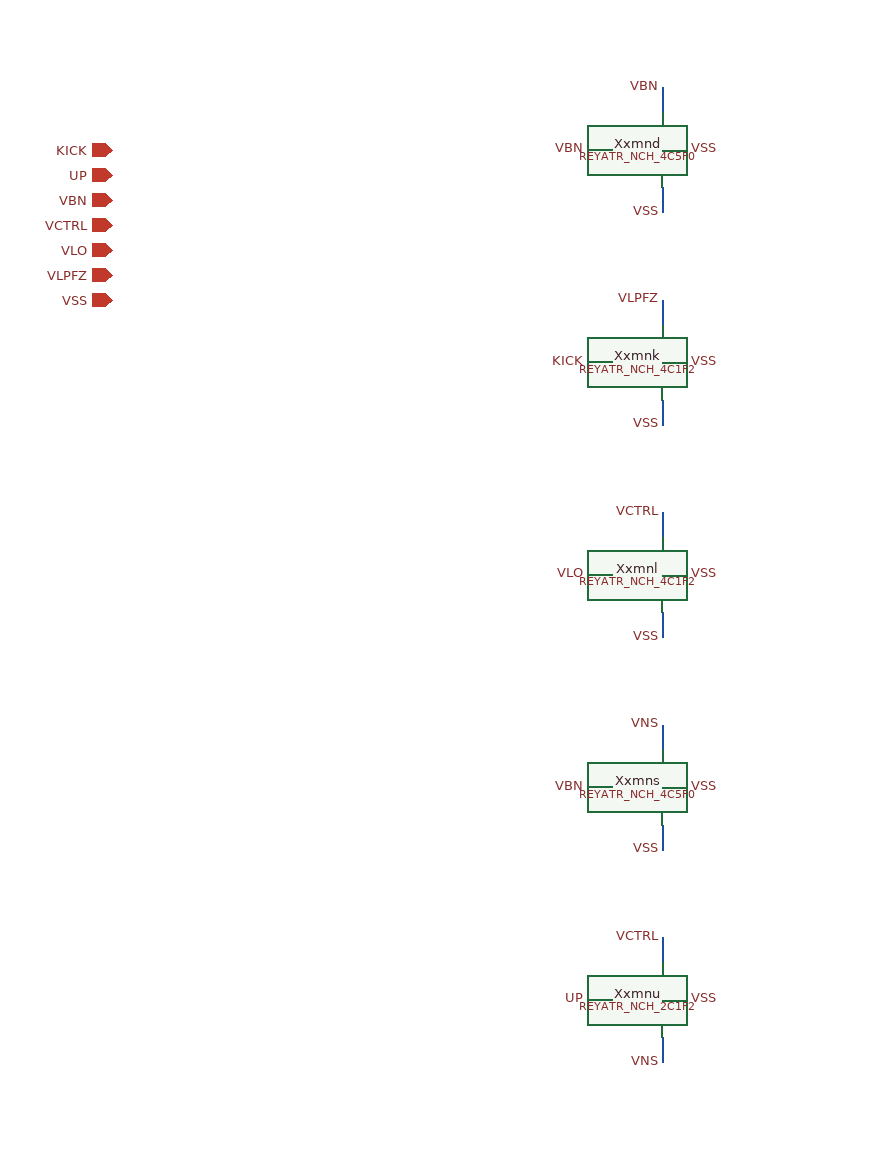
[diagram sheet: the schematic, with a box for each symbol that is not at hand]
v {xschem version=3.0.0 file_version=1.2 }
G {}
K {}
V {}
S {}
E {}
C {devices/iopin.sym} 0 0 0 0 {name=p0 lab=KICK}
C {devices/iopin.sym} 0 20 0 0 {name=p1 lab=UP}
C {devices/iopin.sym} 0 40 0 0 {name=p2 lab=VBN}
C {devices/iopin.sym} 0 60 0 0 {name=p3 lab=VCTRL}
C {devices/iopin.sym} 0 80 0 0 {name=p4 lab=VLO}
C {devices/iopin.sym} 0 100 0 0 {name=p5 lab=VLPFZ}
C {devices/iopin.sym} 0 120 0 0 {name=p6 lab=VSS}
C {REY_ATR_SKY130A/REYATR_NCH_4C5F0.sym} 400 0 0 0 {name=Xxmnd}
N 440.0 -50.0 440.0 -30.0 {lab=VBN}
C {devices/lab_pin.sym} 440.0 -50.0 3 0 {name=l0 sig_type=std_logic lab=VBN }
N 380.0 0.0 400.0 0.0 {lab=VBN}
C {devices/lab_pin.sym} 380.0 0.0 0 0 {name=l1 sig_type=std_logic lab=VBN }
N 440.0 50.0 440.0 30.0 {lab=VSS}
C {devices/lab_pin.sym} 440.0 50.0 1 0 {name=l2 sig_type=std_logic lab=VSS }
N 460.0 0.0 440.0 0.0 {lab=VSS}
C {devices/lab_pin.sym} 460.0 0.0 2 0 {name=l3 sig_type=std_logic lab=VSS }
C {REY_ATR_SKY130A/REYATR_NCH_4C1F2.sym} 400 170 0 0 {name=Xxmnk}
N 440.0 120.0 440.0 140.0 {lab=VLPFZ}
C {devices/lab_pin.sym} 440.0 120.0 3 0 {name=l4 sig_type=std_logic lab=VLPFZ }
N 380.0 170.0 400.0 170.0 {lab=KICK}
C {devices/lab_pin.sym} 380.0 170.0 0 0 {name=l5 sig_type=std_logic lab=KICK }
N 440.0 220.0 440.0 200.0 {lab=VSS}
C {devices/lab_pin.sym} 440.0 220.0 1 0 {name=l6 sig_type=std_logic lab=VSS }
N 460.0 170.0 440.0 170.0 {lab=VSS}
C {devices/lab_pin.sym} 460.0 170.0 2 0 {name=l7 sig_type=std_logic lab=VSS }
C {REY_ATR_SKY130A/REYATR_NCH_4C1F2.sym} 400 340 0 0 {name=Xxmnl}
N 440.0 290.0 440.0 310.0 {lab=VCTRL}
C {devices/lab_pin.sym} 440.0 290.0 3 0 {name=l8 sig_type=std_logic lab=VCTRL }
N 380.0 340.0 400.0 340.0 {lab=VLO}
C {devices/lab_pin.sym} 380.0 340.0 0 0 {name=l9 sig_type=std_logic lab=VLO }
N 440.0 390.0 440.0 370.0 {lab=VSS}
C {devices/lab_pin.sym} 440.0 390.0 1 0 {name=l10 sig_type=std_logic lab=VSS }
N 460.0 340.0 440.0 340.0 {lab=VSS}
C {devices/lab_pin.sym} 460.0 340.0 2 0 {name=l11 sig_type=std_logic lab=VSS }
C {REY_ATR_SKY130A/REYATR_NCH_4C5F0.sym} 400 510 0 0 {name=Xxmns}
N 440.0 460.0 440.0 480.0 {lab=VNS}
C {devices/lab_pin.sym} 440.0 460.0 3 0 {name=l12 sig_type=std_logic lab=VNS }
N 380.0 510.0 400.0 510.0 {lab=VBN}
C {devices/lab_pin.sym} 380.0 510.0 0 0 {name=l13 sig_type=std_logic lab=VBN }
N 440.0 560.0 440.0 540.0 {lab=VSS}
C {devices/lab_pin.sym} 440.0 560.0 1 0 {name=l14 sig_type=std_logic lab=VSS }
N 460.0 510.0 440.0 510.0 {lab=VSS}
C {devices/lab_pin.sym} 460.0 510.0 2 0 {name=l15 sig_type=std_logic lab=VSS }
C {REY_ATR_SKY130A/REYATR_NCH_2C1F2.sym} 400 680 0 0 {name=Xxmnu}
N 440.0 630.0 440.0 650.0 {lab=VCTRL}
C {devices/lab_pin.sym} 440.0 630.0 3 0 {name=l16 sig_type=std_logic lab=VCTRL }
N 380.0 680.0 400.0 680.0 {lab=UP}
C {devices/lab_pin.sym} 380.0 680.0 0 0 {name=l17 sig_type=std_logic lab=UP }
N 440.0 730.0 440.0 710.0 {lab=VNS}
C {devices/lab_pin.sym} 440.0 730.0 1 0 {name=l18 sig_type=std_logic lab=VNS }
N 460.0 680.0 440.0 680.0 {lab=VSS}
C {devices/lab_pin.sym} 460.0 680.0 2 0 {name=l19 sig_type=std_logic lab=VSS }
